! (c) 2009  Infineon Technologies AG, Munich
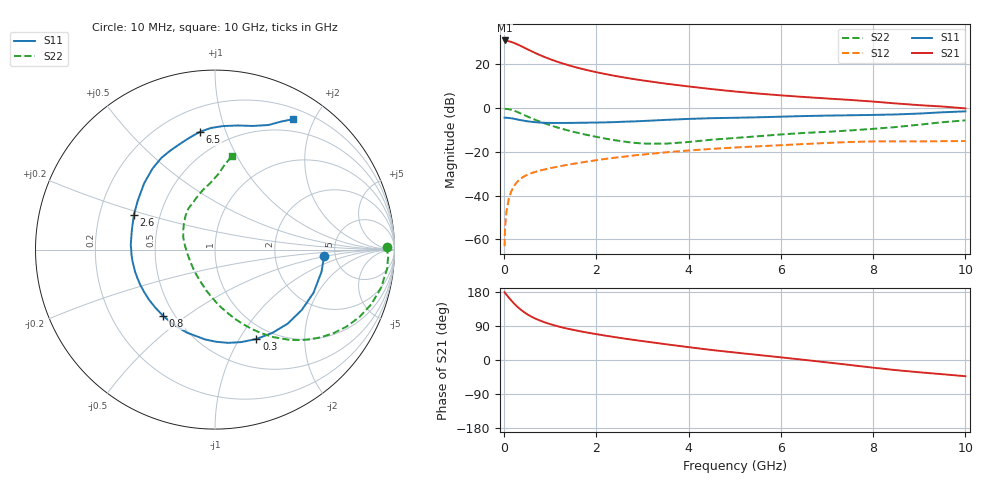
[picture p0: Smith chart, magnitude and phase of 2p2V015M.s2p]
! Infineon Technologies  Discrete & RF Semiconductors
! BFP420
! VCE =  2.0 V,  IC =  15 mA
! Common Emitter S-Parameters:  Nov 2009
# GHz  S  MA  R  50
!  f  S11  S21  S12  S22
! GHz  MAG  ANG  MAG  ANG  MAG  ANG  MAG  ANG
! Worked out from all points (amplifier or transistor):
!   46 points, 10 MHz to 10 GHz, reference 50 ohm
!   highest |S21| = 31.0 dB at 10 MHz (marker M1)
!   |S21| within 3 dB of that: start of sweep to 406.8 MHz
!   unconditionally stable (mu >= 1): 2.008 GHz to end of sweep
!   at 300 MHz: K = 0.26, MSG = 31.2 dB, |S12| = -33.3 dB
!   at 1.7 GHz: K = 0.93, MSG = 21.3 dB, |S12| = -24.7 dB
!   at 10 GHz: K = 1.07, MAG = 5.8 dB, |S12| = -15.0 dB
!   lowest NFmin = 1.06 dB at 900 MHz
!   S11 on the Smith chart (normalised r, x): 10 MHz: 4.06, -0.48; 300 MHz: 0.83, -1.19; 800 MHz: 0.43, -0.41; 2.6 GHz: 0.35, +0.18; 6.5 GHz: 0.35, +0.82; 10 GHz: 0.33, +1.72
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0.01  0.6091 -3.5  35.47 179.2  0.0007 126.9  0.9558 1.0
0.02  0.6077 -4.6  34.71 176.9  0.0019 87.1  0.9655 -2.3
0.05  0.6061 -11.7  34.55 172.2  0.0043 84.0  0.9649 -6.3
0.1  0.5994 -23.6  34.03 164.8  0.0084 80.7  0.9495 -12.9
0.15  0.589 -34.8  32.93 157.6  0.0122 76.0  0.9229 -19.2
0.2  0.5781 -45.5  31.6 151.0  0.0157 71.7  0.8883 -25.0
0.25  0.5632 -55.6  29.97 144.7  0.0188 68.2  0.8497 -30.3
0.3  0.5488 -65.1  28.46 139.0  0.0216 64.8  0.8079 -35.2
0.4  0.5248 -82.0  25.32 129.1  0.0263 59.6  0.7258 -43.6
0.5  0.5035 -96.3  22.43 120.8  0.03 55.9  0.6504 -50.6
0.6  0.4884 -108.7  19.94 113.8  0.033 53.3  0.5852 -56.4
0.8  0.4691 -128.1  16 103.0  0.0381 50.3  0.4825 -65.6
1  0.4617 -143.2  13.2 94.6  0.0426 48.8  0.4073 -73.2
1.2  0.4604 -154.9  11.13 87.8  0.0469 48.0  0.351 -80.0
1.7  0.4659 -176.4  7.887 74.6  0.058 46.3  0.2582 -95.7
2.6  0.4916 156.8  5.048 56.7  0.0782 41.5  0.1724 -128.1
3.5  0.5407 136.9  3.654 41.7  0.0978 34.9  0.1546 -168.6
5.5  0.6201 108.5  2.167 13.4  0.1345 18.3  0.2285 138.9
6.5  0.6619 97.2  1.806 0.4  0.1516 9.7  0.2722 123.1
7  0.6781 91.9  1.669 -6.3  0.1606 5.0  0.2883 115.5
8.5  0.7208 72.9  1.285 -26.8  0.1743 -11.5  0.3716 94.1
10  0.8475 59.0  0.99 -42.8  0.1776 -22.4  0.5285 79.8
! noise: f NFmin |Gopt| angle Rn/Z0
0.9  1.06  0.09  -152  0.13
1.8  1.36  0.18  -147  0.12
2.4  1.49  0.17  -148  0.14
3  1.53  0.25  -138  0.14
4  1.67  0.38  -119  0.2
5  2.14  0.44  -103  0.32
6  2.48  0.5  -88  0.47
